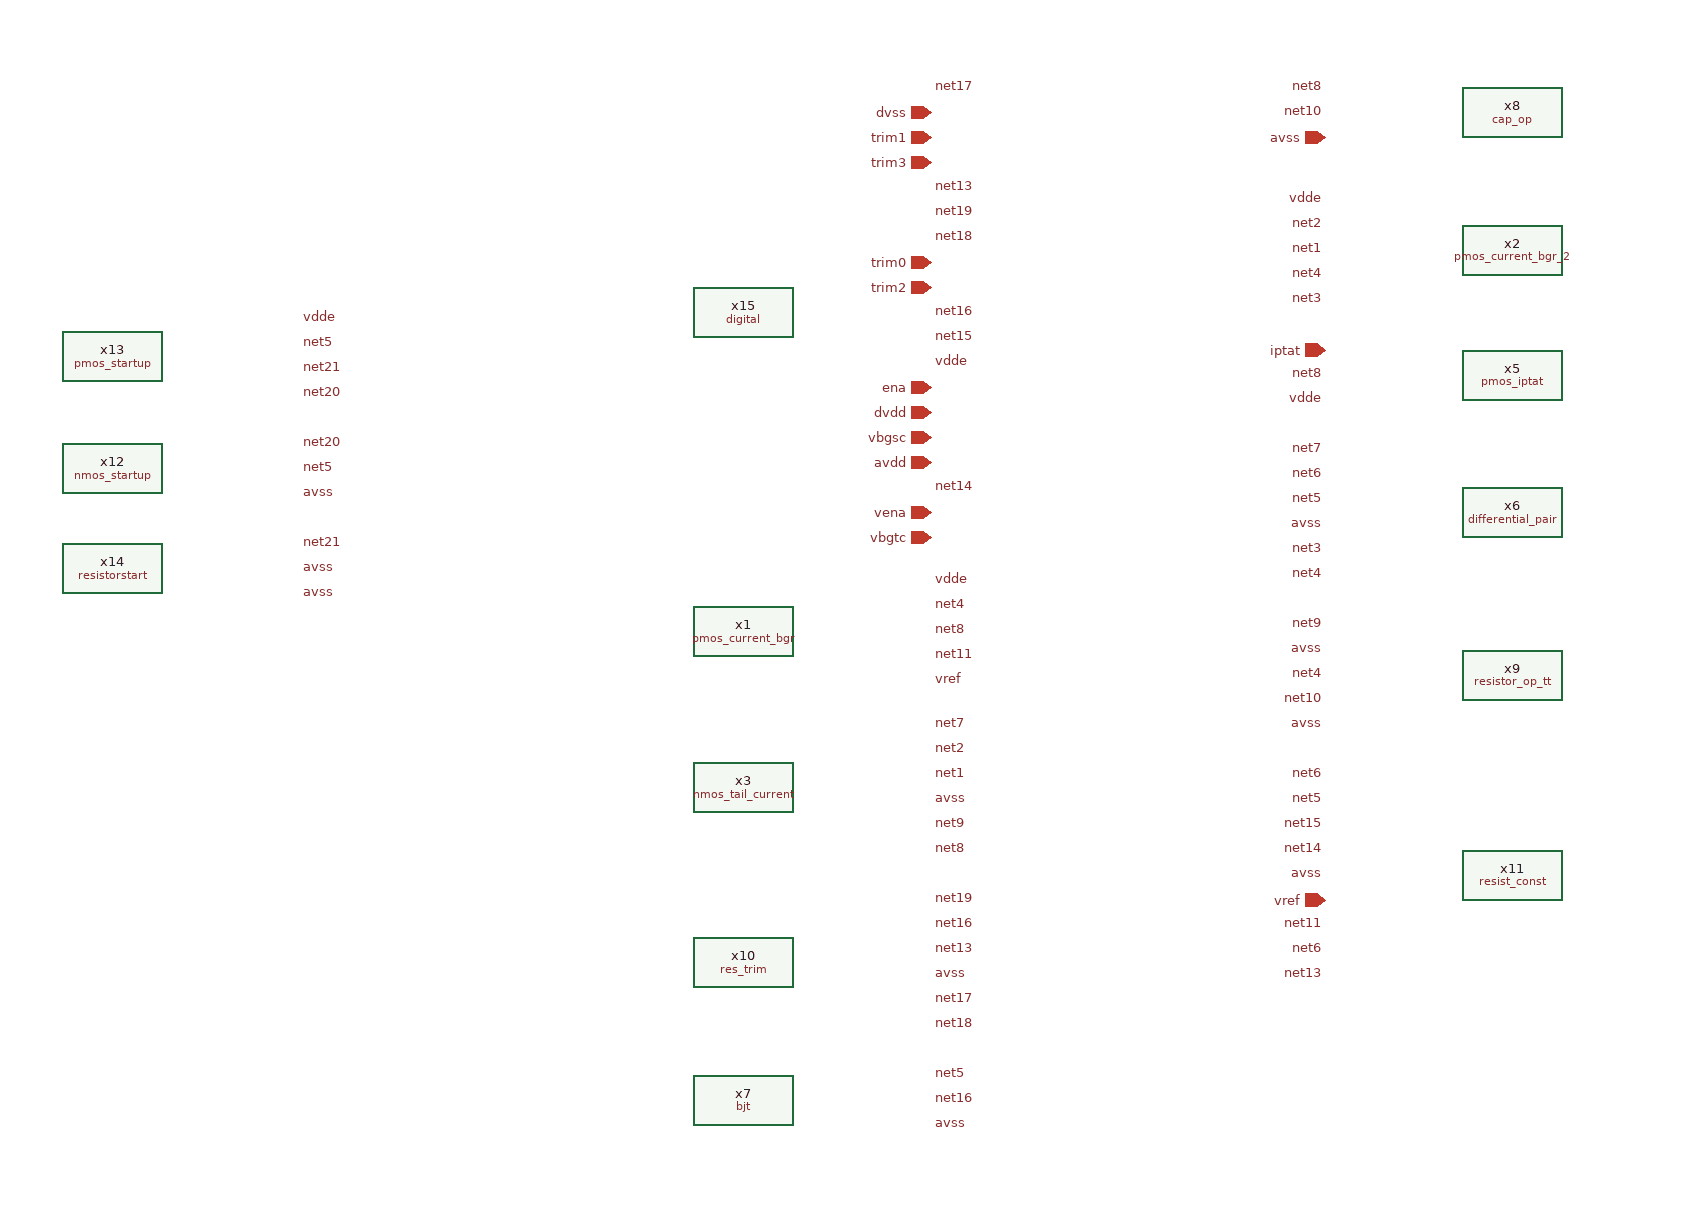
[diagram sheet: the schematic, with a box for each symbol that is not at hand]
v {xschem version=3.4.5 file_version=1.2
}
G {}
K {}
V {}
S {}
E {}
C {/home/gilang_fajrul/chipalooza/sky130_gff_ip__bgr_1.2v/magic/pmos_current_bgr.sym} 855 -920 0 0 {name=x1}
C {/home/gilang_fajrul/chipalooza/sky130_gff_ip__bgr_1.2v/magic/pmos_current_bgr_2.sym} 1470 -1225 0 1 {name=x2}
C {/home/gilang_fajrul/chipalooza/sky130_gff_ip__bgr_1.2v/magic/nmos_tail_current.sym} 855 -795 0 0 {name=x3}
C {/home/gilang_fajrul/chipalooza/sky130_gff_ip__bgr_1.2v/magic/pmos_iptat.sym} 1470 -1125 2 0 {name=x5}
C {/home/gilang_fajrul/chipalooza/sky130_gff_ip__bgr_1.2v/magic/differential_pair.sym} 1470 -1015 2 0 {name=x6}
C {/home/gilang_fajrul/chipalooza/sky130_gff_ip__bgr_1.2v/magic/bjt.sym} 855 -545 0 0 {name=x7}
C {/home/gilang_fajrul/chipalooza/sky130_gff_ip__bgr_1.2v/magic/cap_op.sym} 1470 -1335 2 0 {name=x8}
C {/home/gilang_fajrul/chipalooza/sky130_gff_ip__bgr_1.2v/magic/resistor_op_tt.sym} 1470 -885 2 0 {name=x9}
C {/home/gilang_fajrul/chipalooza/sky130_gff_ip__bgr_1.2v/magic/res_trim.sym} 855 -655 0 0 {name=x10}
C {/home/gilang_fajrul/chipalooza/sky130_gff_ip__bgr_1.2v/magic/resist_const.sym} 1470 -725 2 0 {name=x11}
C {/home/gilang_fajrul/chipalooza/sky130_gff_ip__bgr_1.2v/magic/nmos_startup.sym} 350 -1050 0 0 {name=x12}
C {/home/gilang_fajrul/chipalooza/sky130_gff_ip__bgr_1.2v/magic/pmos_startup.sym} 350 -1140 0 0 {name=x13}
C {/home/gilang_fajrul/chipalooza/sky130_gff_ip__bgr_1.2v/magic/resistorstart.sym} 350 -970 0 0 {name=x14}
C {/home/gilang_fajrul/chipalooza/sky130_gff_ip__bgr_1.2v/magic/digital.sym} 855 -1175 0 0 {name=x15}
C {devices/lab_pin.sym} 1320 -1225 0 0 {name=p1 sig_type=std_logic lab=net1}
C {devices/lab_pin.sym} 1005 -805 2 0 {name=p2 sig_type=std_logic lab=net1}
C {devices/lab_pin.sym} 1320 -1245 0 0 {name=p3 sig_type=std_logic lab=net2}
C {devices/lab_pin.sym} 1005 -825 2 0 {name=p4 sig_type=std_logic lab=net2}
C {devices/lab_pin.sym} 1320 -1185 0 0 {name=p5 sig_type=std_logic lab=net3}
C {devices/lab_pin.sym} 1320 -985 0 0 {name=p6 sig_type=std_logic lab=net3}
C {devices/lab_pin.sym} 1320 -1205 0 0 {name=p7 sig_type=std_logic lab=net4}
C {devices/lab_pin.sym} 1320 -965 0 0 {name=p8 sig_type=std_logic lab=net4}
C {devices/lab_pin.sym} 1320 -1265 0 0 {name=p9 sig_type=std_logic lab=vdde}
C {devices/lab_pin.sym} 1005 -1135 2 0 {name=p10 sig_type=std_logic lab=vdde}
C {devices/lab_pin.sym} 1005 -960 2 0 {name=p11 sig_type=std_logic lab=vdde}
C {devices/lab_pin.sym} 1320 -1105 0 0 {name=p12 sig_type=std_logic lab=vdde}
C {devices/lab_pin.sym} 500 -1170 2 0 {name=p13 sig_type=std_logic lab=vdde}
C {devices/lab_pin.sym} 500 -950 2 0 {name=p14 sig_type=std_logic lab=avss}
C {devices/lab_pin.sym} 500 -1030 2 0 {name=p15 sig_type=std_logic lab=avss}
C {devices/lab_pin.sym} 1005 -645 2 0 {name=p16 sig_type=std_logic lab=avss}
C {devices/lab_pin.sym} 1005 -525 2 0 {name=p17 sig_type=std_logic lab=avss}
C {devices/lab_pin.sym} 1320 -725 0 0 {name=p18 sig_type=std_logic lab=avss}
C {devices/lab_pin.sym} 1320 -1025 0 0 {name=p19 sig_type=std_logic lab=net5}
C {devices/lab_pin.sym} 1320 -1005 0 0 {name=p20 sig_type=std_logic lab=avss}
C {devices/lab_pin.sym} 1005 -565 2 0 {name=p21 sig_type=std_logic lab=net5}
C {devices/lab_pin.sym} 1320 -1045 0 0 {name=p23 sig_type=std_logic lab=net6}
C {devices/lab_pin.sym} 1320 -1065 0 0 {name=p24 sig_type=std_logic lab=net7}
C {devices/lab_pin.sym} 1005 -845 2 0 {name=p25 sig_type=std_logic lab=net7}
C {devices/lab_pin.sym} 1005 -785 2 0 {name=p26 sig_type=std_logic lab=avss}
C {devices/lab_pin.sym} 1005 -745 2 0 {name=p27 sig_type=std_logic lab=net8}
C {devices/lab_pin.sym} 1005 -920 2 0 {name=p28 sig_type=std_logic lab=net8}
C {devices/lab_pin.sym} 1005 -765 2 0 {name=p29 sig_type=std_logic lab=net9}
C {devices/lab_pin.sym} 1320 -925 0 0 {name=p30 sig_type=std_logic lab=net9}
C {devices/lab_pin.sym} 1320 -845 0 0 {name=p31 sig_type=std_logic lab=avss}
C {devices/lab_pin.sym} 1320 -905 0 0 {name=p32 sig_type=std_logic lab=avss}
C {devices/lab_pin.sym} 1005 -940 2 0 {name=p33 sig_type=std_logic lab=net4}
C {devices/lab_pin.sym} 1320 -885 0 0 {name=p34 sig_type=std_logic lab=net4}
C {devices/lab_pin.sym} 1320 -1355 0 0 {name=p35 sig_type=std_logic lab=net8}
C {devices/lab_pin.sym} 1320 -865 0 0 {name=p36 sig_type=std_logic lab=net10}
C {devices/lab_pin.sym} 1320 -1335 0 0 {name=p37 sig_type=std_logic lab=net10}
C {devices/lab_pin.sym} 1320 -1125 0 0 {name=p41 sig_type=std_logic lab=net8}
C {devices/lab_pin.sym} 1005 -900 2 0 {name=p43 sig_type=std_logic lab=net11}
C {devices/lab_pin.sym} 1320 -685 0 0 {name=p44 sig_type=std_logic lab=net11}
C {devices/lab_pin.sym} 1005 -880 2 0 {name=p46 sig_type=std_logic lab=vref}
C {devices/lab_pin.sym} 1320 -785 0 0 {name=p47 sig_type=std_logic lab=net5}
C {devices/lab_pin.sym} 1320 -805 0 0 {name=p48 sig_type=std_logic lab=net6}
C {devices/lab_pin.sym} 1320 -665 0 0 {name=p22 sig_type=std_logic lab=net6}
C {devices/lab_pin.sym} 1320 -645 0 0 {name=p49 sig_type=std_logic lab=net13}
C {devices/lab_pin.sym} 1005 -665 2 0 {name=p50 sig_type=std_logic lab=net13}
C {devices/lab_pin.sym} 1005 -1035 2 0 {name=p52 sig_type=std_logic lab=net14}
C {devices/lab_pin.sym} 1320 -745 0 0 {name=p53 sig_type=std_logic lab=net14}
C {devices/lab_pin.sym} 1320 -765 0 0 {name=p54 sig_type=std_logic lab=net15}
C {devices/lab_pin.sym} 1005 -1155 2 0 {name=p55 sig_type=std_logic lab=net15}
C {devices/lab_pin.sym} 1005 -685 2 0 {name=p56 sig_type=std_logic lab=net16}
C {devices/lab_pin.sym} 1005 -545 2 0 {name=p57 sig_type=std_logic lab=net16}
C {devices/lab_pin.sym} 1005 -1275 2 0 {name=p60 sig_type=std_logic lab=net13}
C {devices/lab_pin.sym} 1005 -1175 2 0 {name=p61 sig_type=std_logic lab=net16}
C {devices/lab_pin.sym} 1005 -625 2 0 {name=p62 sig_type=std_logic lab=net17}
C {devices/lab_pin.sym} 1005 -1355 2 0 {name=p63 sig_type=std_logic lab=net17}
C {devices/lab_pin.sym} 1005 -1235 2 0 {name=p64 sig_type=std_logic lab=net18}
C {devices/lab_pin.sym} 1005 -605 2 0 {name=p65 sig_type=std_logic lab=net18}
C {devices/lab_pin.sym} 1005 -705 2 0 {name=p66 sig_type=std_logic lab=net19}
C {devices/lab_pin.sym} 1005 -1255 2 0 {name=p67 sig_type=std_logic lab=net19}
C {devices/lab_pin.sym} 500 -1110 2 0 {name=p68 sig_type=std_logic lab=net20}
C {devices/lab_pin.sym} 500 -1070 2 0 {name=p69 sig_type=std_logic lab=net20}
C {devices/lab_pin.sym} 500 -1130 2 0 {name=p70 sig_type=std_logic lab=net21}
C {devices/lab_pin.sym} 500 -990 2 0 {name=p71 sig_type=std_logic lab=net21}
C {devices/lab_pin.sym} 500 -970 2 0 {name=p72 sig_type=std_logic lab=avss}
C {devices/iopin.sym} 1005 -1315 0 0 {name=p75 lab=trim1}
C {devices/iopin.sym} 1005 -1295 0 0 {name=p76 lab=trim3}
C {devices/iopin.sym} 1005 -1215 0 0 {name=p77 lab=trim0}
C {devices/iopin.sym} 1005 -1195 0 0 {name=p78 lab=trim2}
C {devices/iopin.sym} 1005 -1095 0 0 {name=p58 lab=dvdd}
C {devices/iopin.sym} 1005 -1075 0 0 {name=p79 lab=vbgsc}
C {devices/iopin.sym} 1005 -995 0 0 {name=p80 lab=vbgtc}
C {devices/iopin.sym} 1005 -1055 0 0 {name=p39 lab=avdd}
C {devices/iopin.sym} 1005 -1015 0 0 {name=p51 lab=vena}
C {devices/iopin.sym} 1005 -1115 0 0 {name=p59 lab=ena}
C {devices/iopin.sym} 1320 -1315 2 0 {name=p38 lab=avss}
C {devices/iopin.sym} 1005 -1335 0 0 {name=p40 lab=dvss}
C {devices/iopin.sym} 1320 -1145 2 0 {name=p42 lab=iptat}
C {devices/iopin.sym} 1320 -705 2 0 {name=p45 lab=vref}
C {devices/lab_pin.sym} 500 -1150 2 0 {name=p81 sig_type=std_logic lab=net5}
C {devices/lab_pin.sym} 500 -1050 2 0 {name=p73 sig_type=std_logic lab=net5}
